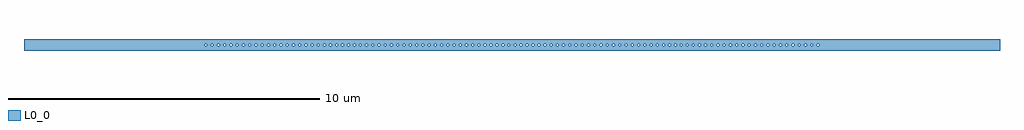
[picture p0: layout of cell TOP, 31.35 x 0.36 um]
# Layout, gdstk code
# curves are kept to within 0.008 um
import gdstk
lib = gdstk.Library(unit=1e-6, precision=1e-09)
def P(c, l, *ps):  # polygons
    for p in ps: c.add(gdstk.Polygon(p, *l))
L0_0 = (0, 0)

top = lib.new_cell('TOP')
P(top, L0_0, [(0,0),(0,0),(0,0),(0,0)],
  [(-8.214,0.035),(-8.189,0.012),(-8.189,-0.012),(-8.227,-0.036),(-8.26,-0.006),(-8.256,0.017),(-8.227,0.036),(-8.428,0.036),(-8.396,0.022),(-8.388,0),(-8.396,-0.022),(-8.428,-0.036),(-8.461,-0.006),(-8.457,0.017),(-8.428,0.036),(-8.629,0.036),(-8.597,0.022),(-8.589,0),(-8.597,-0.022),(-8.629,-0.036),(-8.662,-0.006),(-8.658,0.017),(-8.629,0.036),(-8.83,0.036),(-8.798,0.022),(-8.79,0),(-8.798,-0.022),(-8.83,-0.036),(-8.863,-0.006),(-8.859,0.017),(-8.83,0.036),(-9.031,0.036),(-8.999,0.022),(-8.991,0),(-8.999,-0.022),(-9.031,-0.036),(-9.064,-0.006),(-9.06,0.017),(-9.031,0.036),(-9.232,0.036),(-9.2,0.022),(-9.192,0),(-9.2,-0.022),(-9.232,-0.036),(-9.265,-0.006),(-9.261,0.017),(-9.232,0.036),(-9.433,0.036),(-9.401,0.022),(-9.393,0),(-9.401,-0.022),(-9.433,-0.036),(-9.466,-0.006),(-9.462,0.017),(-9.433,0.036),(-9.634,0.036),(-9.602,0.022),(-9.594,0),(-9.602,-0.022),(-9.634,-0.036),(-9.667,-0.006),(-9.663,0.017),(-9.634,0.036),(-9.835,0.036),(-9.803,0.022),(-9.795,0),(-9.803,-0.022),(-9.835,-0.036),(-9.868,-0.006),(-9.864,0.017),(-9.835,0.036),(-15.675,0.036),(-15.675,-0.181),(-8.026,-0.181),(-8.026,-0.036),(-8.059,-0.006),(-8.055,0.017),(-8.026,0.036),(-8.026,0.181),(-15.675,0.181),(-15.675,0.036)],
  [(-6.21,0.035),(-6.21,0.181),(-8.026,0.181),(-8.026,0.036),(-6.223,0.036)],
  [(-6.21,-0.035),(-6.234,-0.034),(-6.255,-0.006),(-6.252,0.017),(-6.223,0.036),(-6.421,0.036),(-6.389,0.022),(-6.382,0),(-6.389,-0.022),(-6.421,-0.036),(-6.443,-0.027),(-6.454,-0.006),(-6.443,0.027),(-6.421,0.036),(-6.62,0.036),(-6.597,0.03),(-6.581,0),(-6.597,-0.03),(-6.62,-0.036),(-6.642,-0.027),(-6.653,-0.006),(-6.642,0.027),(-6.62,0.036),(-6.821,0.036),(-6.789,0.022),(-6.781,0),(-6.789,-0.022),(-6.821,-0.036),(-6.853,-0.006),(-6.85,0.017),(-6.821,0.036),(-7.021,0.036),(-6.989,0.022),(-6.982,0),(-6.989,-0.022),(-7.021,-0.036),(-7.043,-0.027),(-7.054,-0.006),(-7.043,0.027),(-7.021,0.036),(-7.222,0.036),(-7.19,0.022),(-7.183,0),(-7.19,-0.022),(-7.222,-0.036),(-7.244,-0.027),(-7.255,-0.006),(-7.244,0.027),(-7.222,0.036),(-7.423,0.036),(-7.391,0.022),(-7.384,0),(-7.391,-0.022),(-7.423,-0.036),(-7.445,-0.027),(-7.456,-0.006),(-7.445,0.027),(-7.423,0.036),(-7.624,0.036),(-7.592,0.022),(-7.584,0),(-7.592,-0.022),(-7.624,-0.036),(-7.657,-0.006),(-7.653,0.017),(-7.624,0.036),(-7.825,0.036),(-7.793,0.022),(-7.785,0),(-7.793,-0.022),(-7.825,-0.036),(-7.858,-0.006),(-7.854,0.017),(-7.825,0.036),(-8.026,0.036),(-7.994,0.022),(-7.986,0),(-7.994,-0.022),(-8.026,-0.036),(-8.026,-0.181),(-6.21,-0.181)],
  [(-4.461,0.035),(-4.461,0.181),(-6.21,0.181),(-6.21,0.036),(-4.473,0.036)],
  [(-4.461,-0.035),(-4.485,-0.034),(-4.506,-0.006),(-4.495,0.027),(-4.473,0.036),(-4.674,0.036),(-4.642,0.022),(-4.635,0),(-4.642,-0.022),(-4.674,-0.036),(-4.696,-0.027),(-4.707,-0.006),(-4.696,0.027),(-4.674,0.036),(-4.875,0.036),(-4.843,0.022),(-4.836,0),(-4.843,-0.022),(-4.875,-0.036),(-4.897,-0.027),(-4.908,-0.006),(-4.897,0.027),(-4.875,0.036),(-5.064,0.036),(-5.032,0.022),(-5.025,0),(-5.032,-0.022),(-5.064,-0.036),(-5.086,-0.027),(-5.097,-0.006),(-5.086,0.027),(-5.064,0.036),(-5.254,0.036),(-5.222,0.022),(-5.214,0),(-5.222,-0.022),(-5.254,-0.036),(-5.286,-0.006),(-5.283,0.017),(-5.254,0.036),(-5.444,0.036),(-5.412,0.022),(-5.405,0),(-5.412,-0.022),(-5.444,-0.036),(-5.466,-0.027),(-5.477,-0.006),(-5.466,0.027),(-5.444,0.036),(-5.636,0.036),(-5.604,0.022),(-5.597,0),(-5.604,-0.022),(-5.636,-0.036),(-5.658,-0.027),(-5.669,-0.006),(-5.658,0.027),(-5.636,0.036),(-5.83,0.036),(-5.798,0.022),(-5.791,0),(-5.798,-0.022),(-5.83,-0.036),(-5.852,-0.027),(-5.863,-0.006),(-5.852,0.027),(-5.83,0.036),(-6.025,0.036),(-6.002,0.03),(-5.986,0),(-6.002,-0.03),(-6.025,-0.036),(-6.047,-0.027),(-6.058,-0.006),(-6.047,0.027),(-6.025,0.036),(-6.21,0.036),(-6.183,0),(-6.21,-0.035),(-6.21,-0.181),(-4.461,-0.181)],
  [(-2.853,0.035),(-2.827,0.012),(-2.827,-0.012),(-2.865,-0.036),(-2.887,-0.027),(-2.898,-0.006),(-2.887,0.027),(-2.865,0.036),(-3.066,0.036),(-3.034,0.022),(-3.027,0),(-3.034,-0.022),(-3.066,-0.036),(-3.088,-0.027),(-3.099,-0.006),(-3.088,0.027),(-3.066,0.036),(-3.267,0.036),(-3.235,0.022),(-3.228,0),(-3.235,-0.022),(-3.267,-0.036),(-3.289,-0.027),(-3.3,-0.006),(-3.289,0.027),(-3.267,0.036),(-3.468,0.036),(-3.436,0.022),(-3.429,0),(-3.436,-0.022),(-3.468,-0.036),(-3.49,-0.027),(-3.501,-0.006),(-3.49,0.027),(-3.468,0.036),(-3.669,0.036),(-3.637,0.022),(-3.63,0),(-3.637,-0.022),(-3.669,-0.036),(-3.691,-0.027),(-3.702,-0.006),(-3.691,0.027),(-3.669,0.036),(-3.87,0.036),(-3.838,0.022),(-3.831,0),(-3.838,-0.022),(-3.87,-0.036),(-3.892,-0.027),(-3.903,-0.006),(-3.892,0.027),(-3.87,0.036),(-4.071,0.036),(-4.039,0.022),(-4.032,0),(-4.039,-0.022),(-4.071,-0.036),(-4.093,-0.027),(-4.104,-0.006),(-4.093,0.027),(-4.071,0.036),(-4.272,0.036),(-4.24,0.022),(-4.233,0),(-4.24,-0.022),(-4.272,-0.036),(-4.294,-0.027),(-4.305,-0.006),(-4.294,0.027),(-4.272,0.036),(-4.461,0.036),(-4.434,0),(-4.461,-0.035),(-4.461,-0.181),(-2.664,-0.181),(-2.664,-0.036),(-2.686,-0.027),(-2.697,-0.006),(-2.686,0.027),(-2.664,0.036),(-2.664,0.181),(-4.461,0.181),(-4.461,0.036)],
  [(-0.858,0.035),(-0.858,0.181),(-2.664,0.181),(-2.664,0.036),(-0.87,0.036)],
  [(-0.858,-0.035),(-0.882,-0.034),(-0.903,-0.006),(-0.892,0.027),(-0.87,0.036),(-1.066,0.036),(-1.034,0.022),(-1.027,0),(-1.034,-0.022),(-1.066,-0.036),(-1.088,-0.027),(-1.099,-0.006),(-1.088,0.027),(-1.066,0.036),(-1.263,0.036),(-1.231,0.022),(-1.224,0),(-1.231,-0.022),(-1.263,-0.036),(-1.285,-0.027),(-1.296,-0.006),(-1.285,0.027),(-1.263,0.036),(-1.462,0.036),(-1.43,0.022),(-1.422,0),(-1.43,-0.022),(-1.462,-0.036),(-1.494,-0.006),(-1.491,0.017),(-1.462,0.036),(-1.661,0.036),(-1.629,0.022),(-1.622,0),(-1.629,-0.022),(-1.661,-0.036),(-1.683,-0.027),(-1.694,-0.006),(-1.683,0.027),(-1.661,0.036),(-1.861,0.036),(-1.829,0.022),(-1.822,0),(-1.829,-0.022),(-1.861,-0.036),(-1.883,-0.027),(-1.894,-0.006),(-1.883,0.027),(-1.861,0.036),(-2.062,0.036),(-2.03,0.022),(-2.022,0),(-2.03,-0.022),(-2.062,-0.036),(-2.095,-0.006),(-2.091,0.017),(-2.062,0.036),(-2.262,0.036),(-2.239,0.03),(-2.223,0),(-2.239,-0.03),(-2.262,-0.036),(-2.284,-0.027),(-2.295,-0.006),(-2.284,0.027),(-2.262,0.036),(-2.463,0.036),(-2.44,0.03),(-2.424,0),(-2.44,-0.03),(-2.463,-0.036),(-2.485,-0.027),(-2.496,-0.006),(-2.485,0.027),(-2.463,0.036),(-2.664,0.036),(-2.641,0.03),(-2.625,0),(-2.641,-0.03),(-2.664,-0.036),(-2.664,-0.181),(-0.858,-0.181)],
  [(0.876,0.035),(0.887,0.03),(0.887,0.181),(-0.858,0.181),(-0.858,0.036),(0.864,0.036)],
  [(0.887,-0.03),(0.852,-0.034),(0.831,-0.006),(0.842,0.027),(0.864,0.036),(0.67,0.036),(0.702,0.022),(0.709,0),(0.702,-0.022),(0.67,-0.036),(0.648,-0.027),(0.637,-0.006),(0.648,0.027),(0.67,0.036),(0.478,0.036),(0.51,0.022),(0.517,0),(0.51,-0.022),(0.478,-0.036),(0.456,-0.027),(0.445,-0.006),(0.456,0.027),(0.478,0.036),(0.288,0.036),(0.319,0.022),(0.327,0),(0.319,-0.022),(0.288,-0.036),(0.266,-0.027),(0.255,-0.006),(0.266,0.027),(0.288,0.036),(0.098,0.036),(0.13,0.022),(0.138,0),(0.13,-0.022),(0.098,-0.036),(0.076,-0.027),(0.065,-0.006),(0.076,0.027),(0.098,0.036),(-0.105,0.036),(-0.073,0.022),(-0.065,0),(-0.073,-0.022),(-0.105,-0.036),(-0.127,-0.027),(-0.138,-0.006),(-0.127,0.027),(-0.105,0.036),(-0.294,0.036),(-0.262,0.022),(-0.255,0),(-0.262,-0.022),(-0.294,-0.036),(-0.316,-0.027),(-0.327,-0.006),(-0.316,0.027),(-0.294,0.036),(-0.484,0.036),(-0.461,0.03),(-0.445,0),(-0.461,-0.03),(-0.484,-0.036),(-0.506,-0.027),(-0.517,-0.006),(-0.506,0.027),(-0.484,0.036),(-0.677,0.036),(-0.645,0.022),(-0.637,0),(-0.645,-0.022),(-0.677,-0.036),(-0.709,-0.006),(-0.698,0.027),(-0.677,0.036),(-0.858,0.036),(-0.831,0),(-0.858,-0.035),(-0.858,-0.181),(0.887,-0.181)],
  [(2.67,0.035),(2.67,0.181),(0.887,0.181),(0.887,0.036),(2.658,0.036)],
  [(2.67,-0.035),(2.646,-0.034),(2.625,-0.006),(2.636,0.027),(2.658,0.036),(2.457,0.036),(2.489,0.022),(2.496,0),(2.489,-0.022),(2.457,-0.036),(2.435,-0.027),(2.424,-0.006),(2.435,0.027),(2.457,0.036),(2.256,0.036),(2.288,0.022),(2.295,0),(2.288,-0.022),(2.256,-0.036),(2.234,-0.027),(2.223,-0.006),(2.234,0.027),(2.256,0.036),(2.055,0.036),(2.087,0.022),(2.094,0),(2.087,-0.022),(2.055,-0.036),(2.033,-0.027),(2.022,-0.006),(2.033,0.027),(2.055,0.036),(1.855,0.036),(1.886,0.022),(1.894,0),(1.886,-0.022),(1.855,-0.036),(1.833,-0.027),(1.822,-0.006),(1.833,0.027),(1.855,0.036),(1.654,0.036),(1.686,0.022),(1.694,0),(1.686,-0.022),(1.654,-0.036),(1.622,-0.006),(1.633,0.027),(1.654,0.036),(1.455,0.036),(1.487,0.022),(1.494,0),(1.487,-0.022),(1.455,-0.036),(1.433,-0.027),(1.422,-0.006),(1.433,0.027),(1.455,0.036),(1.257,0.036),(1.288,0.022),(1.296,0),(1.288,-0.022),(1.257,-0.036),(1.235,-0.027),(1.224,-0.006),(1.235,0.027),(1.257,0.036),(1.059,0.036),(1.091,0.022),(1.099,0),(1.091,-0.022),(1.059,-0.036),(1.027,-0.006),(1.038,0.027),(1.059,0.036),(0.887,0.036),(0.903,0),(0.887,-0.03),(0.887,-0.181),(2.67,-0.181)],
  [(4.479,0.035),(4.49,0.03),(4.498,0.022),(4.504,0.012),(4.504,0.181),(2.67,0.181),(2.67,0.036),(4.467,0.036)],
  [(4.504,-0.012),(4.479,-0.035),(4.445,-0.027),(4.434,0.006),(4.445,0.027),(4.467,0.036),(4.266,0.036),(4.289,0.03),(4.305,0),(4.289,-0.03),(4.266,-0.036),(4.244,-0.027),(4.233,-0.006),(4.244,0.027),(4.266,0.036),(4.065,0.036),(4.088,0.03),(4.104,0),(4.088,-0.03),(4.065,-0.036),(4.043,-0.027),(4.032,-0.006),(4.043,0.027),(4.065,0.036),(3.864,0.036),(3.887,0.03),(3.903,0),(3.887,-0.03),(3.864,-0.036),(3.842,-0.027),(3.831,-0.006),(3.842,0.027),(3.864,0.036),(3.663,0.036),(3.686,0.03),(3.702,0),(3.686,-0.03),(3.663,-0.036),(3.641,-0.027),(3.63,-0.006),(3.641,0.027),(3.663,0.036),(3.462,0.036),(3.485,0.03),(3.501,0),(3.485,-0.03),(3.462,-0.036),(3.44,-0.027),(3.429,-0.006),(3.44,0.027),(3.462,0.036),(3.261,0.036),(3.284,0.03),(3.3,0),(3.284,-0.03),(3.261,-0.036),(3.239,-0.027),(3.228,-0.006),(3.239,0.027),(3.261,0.036),(3.06,0.036),(3.083,0.03),(3.099,0),(3.083,-0.03),(3.06,-0.036),(3.038,-0.027),(3.027,-0.006),(3.038,0.027),(3.06,0.036),(2.859,0.036),(2.882,0.03),(2.898,0),(2.882,-0.03),(2.859,-0.036),(2.837,-0.027),(2.826,-0.006),(2.837,0.027),(2.859,0.036),(2.67,0.036),(2.697,0),(2.67,-0.035),(2.67,-0.181),(4.504,-0.181)],
  [(6.228,0.035),(6.239,0.03),(6.248,0.022),(6.254,0.012),(6.254,0.181),(4.504,0.181),(4.504,0.036),(6.216,0.036)],
  [(6.254,-0.012),(6.228,-0.035),(6.194,-0.027),(6.183,0.006),(6.194,0.027),(6.216,0.036),(6.019,0.036),(6.051,0.022),(6.058,0),(6.051,-0.022),(6.019,-0.036),(5.997,-0.027),(5.986,-0.006),(5.997,0.027),(6.019,0.036),(5.823,0.036),(5.855,0.022),(5.863,0),(5.855,-0.022),(5.823,-0.036),(5.79,-0.006),(5.794,0.017),(5.823,0.036),(5.629,0.036),(5.661,0.022),(5.669,0),(5.661,-0.022),(5.629,-0.036),(5.597,-0.006),(5.608,0.027),(5.629,0.036),(5.437,0.036),(5.469,0.022),(5.477,0),(5.469,-0.022),(5.437,-0.036),(5.405,-0.006),(5.416,0.027),(5.437,0.036),(5.247,0.036),(5.279,0.022),(5.286,0),(5.279,-0.022),(5.247,-0.036),(5.225,-0.027),(5.214,-0.006),(5.225,0.027),(5.247,0.036),(5.058,0.036),(5.081,0.03),(5.097,0),(5.081,-0.03),(5.058,-0.036),(5.036,-0.027),(5.025,-0.006),(5.036,0.027),(5.058,0.036),(4.869,0.036),(4.892,0.03),(4.908,0),(4.892,-0.03),(4.869,-0.036),(4.847,-0.027),(4.836,-0.006),(4.847,0.027),(4.869,0.036),(4.668,0.036),(4.691,0.03),(4.707,0),(4.691,-0.03),(4.668,-0.036),(4.646,-0.027),(4.635,-0.006),(4.646,0.027),(4.668,0.036),(4.504,0.036),(4.504,-0.181),(6.254,-0.181)],
  [(8.031,0.035),(8.057,0.012),(8.057,-0.012),(8.019,-0.036),(7.997,-0.027),(7.986,-0.006),(7.997,0.027),(8.019,0.036),(7.818,0.036),(7.85,0.022),(7.857,0),(7.85,-0.022),(7.818,-0.036),(7.796,-0.027),(7.785,-0.006),(7.796,0.027),(7.818,0.036),(7.617,0.036),(7.649,0.022),(7.656,0),(7.649,-0.022),(7.617,-0.036),(7.595,-0.027),(7.584,-0.006),(7.595,0.027),(7.617,0.036),(7.416,0.036),(7.448,0.022),(7.456,0),(7.448,-0.022),(7.416,-0.036),(7.394,-0.027),(7.383,-0.006),(7.394,0.027),(7.416,0.036),(7.215,0.036),(7.247,0.022),(7.255,0),(7.247,-0.022),(7.215,-0.036),(7.183,-0.006),(7.186,0.017),(7.215,0.036),(7.015,0.036),(7.046,0.022),(7.054,0),(7.046,-0.022),(7.015,-0.036),(6.993,-0.027),(6.982,-0.006),(6.993,0.027),(7.015,0.036),(6.814,0.036),(6.846,0.022),(6.853,0),(6.846,-0.022),(6.814,-0.036),(6.792,-0.027),(6.781,-0.006),(6.792,0.027),(6.814,0.036),(6.614,0.036),(6.646,0.022),(6.653,0),(6.646,-0.022),(6.614,-0.036),(6.592,-0.027),(6.581,-0.006),(6.592,0.027),(6.614,0.036),(6.414,0.036),(6.446,0.022),(6.454,0),(6.446,-0.022),(6.414,-0.036),(6.382,-0.006),(6.393,0.027),(6.414,0.036),(6.254,0.036),(6.254,-0.181),(8.187,-0.181),(8.187,0.181),(6.254,0.181),(6.254,0.036)],
  [(8.198,0.027),(8.208,0.034),(8.22,0.036),(8.187,0.036),(8.187,0.006),(8.191,0.017)],
  [(8.232,0.035),(8.252,0.022),(8.258,-0.006),(8.388,-0.006),(8.399,0.027),(8.421,0.036),(8.453,0.022),(8.459,-0.006),(8.589,-0.006),(8.6,0.027),(8.622,0.036),(8.654,0.022),(8.66,-0.006),(8.79,-0.006),(8.801,0.027),(8.823,0.036),(8.855,0.022),(8.861,-0.006),(8.991,-0.006),(9.002,0.027),(9.024,0.036),(9.056,0.022),(9.062,-0.006),(9.192,-0.006),(9.203,0.027),(9.225,0.036),(9.257,0.022),(9.263,-0.006),(9.393,-0.006),(9.404,0.027),(9.426,0.036),(9.458,0.022),(9.464,-0.006),(9.594,-0.006),(9.605,0.027),(9.627,0.036),(9.659,0.022),(9.665,-0.006),(9.795,-0.006),(9.806,0.027),(9.828,0.036),(9.86,0.022),(9.866,-0.012),(9.828,-0.036),(9.806,-0.027),(9.795,-0.006),(9.665,-0.006),(9.65,-0.03),(9.627,-0.036),(9.605,-0.027),(9.594,-0.006),(9.464,-0.006),(9.449,-0.03),(9.426,-0.036),(9.404,-0.027),(9.393,-0.006),(9.263,-0.006),(9.248,-0.03),(9.225,-0.036),(9.203,-0.027),(9.192,-0.006),(9.062,-0.006),(9.047,-0.03),(9.024,-0.036),(9.002,-0.027),(8.991,-0.006),(8.861,-0.006),(8.846,-0.03),(8.823,-0.036),(8.801,-0.027),(8.79,-0.006),(8.66,-0.006),(8.645,-0.03),(8.622,-0.036),(8.6,-0.027),(8.589,-0.006),(8.459,-0.006),(8.444,-0.03),(8.421,-0.036),(8.399,-0.027),(8.388,-0.006),(8.258,-0.006),(8.243,-0.03),(8.22,-0.036),(8.198,-0.027),(8.187,-0.006),(8.187,-0.181),(15.675,-0.181),(15.675,0.181),(8.187,0.181),(8.187,0.036)])

lib.write_gds('TOP.gds')
